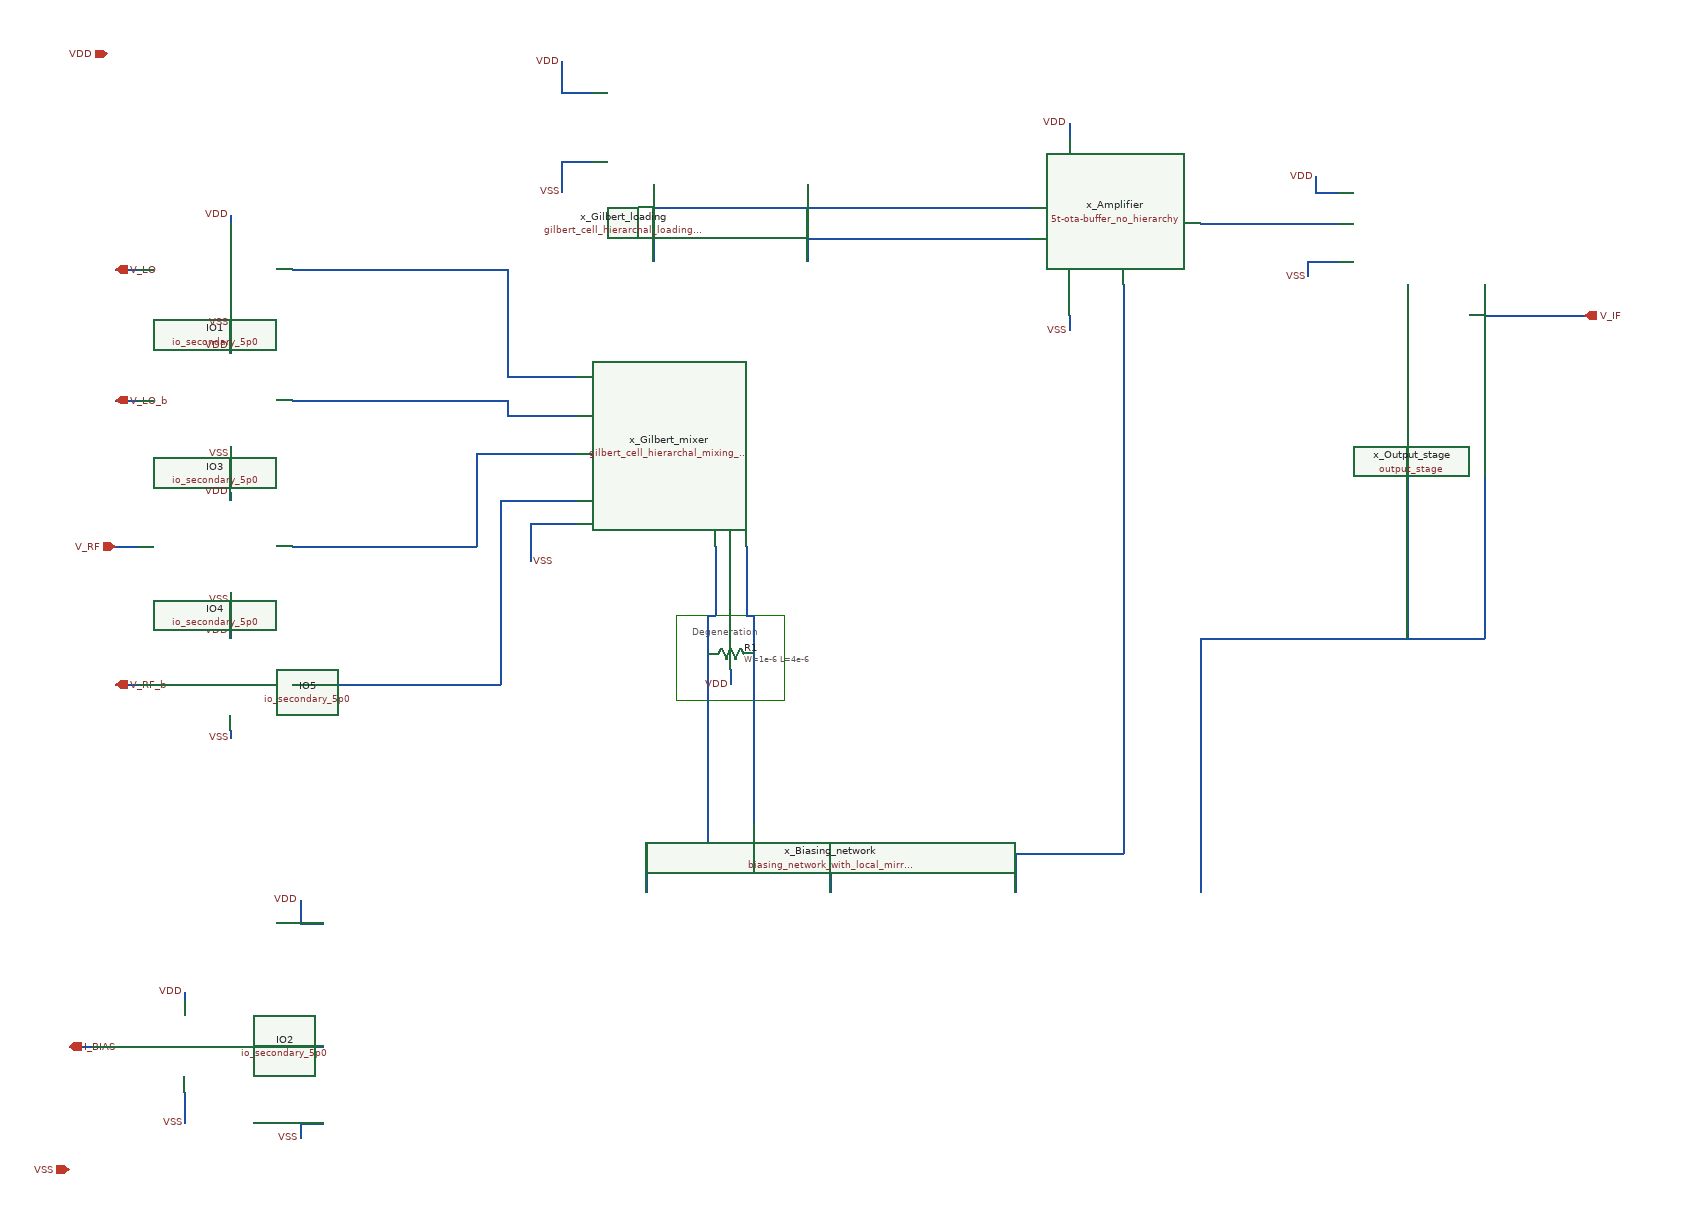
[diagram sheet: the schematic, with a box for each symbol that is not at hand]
v {xschem version=3.4.5 file_version=1.2
}
G {}
K {}
V {}
S {}
E {}
P 4 5 1340 -1230 1480 -1230 1480 -1120 1340 -1120 1340 -1230 {}
T {Degeneration} 1360 -1220 0 0 0.3 0.3 {}
N 1150 -1350 1150 -1300 {
lab=VSS}
N 1390 -1320 1390 -1280 {
lab=#net1}
N 1390 -1280 1390 -1260 {
lab=#net1}
N 1430 -1320 1430 -1260 {
lab=#net2}
N 1310 -1790 1310 -1690 {
lab=#net3}
N 1510 -1790 1510 -1690 {
lab=#net4}
N 1120 -1490 1210 -1490 {
lab=#net5}
N 1120 -1540 1210 -1540 {
lab=#net6}
N 1120 -1440 1210 -1440 {
lab=#net7}
N 1120 -1380 1210 -1380 {
lab=#net8}
N 1150 -1350 1210 -1350 {
lab=VSS}
N 1390 -1260 1390 -1230 {
lab=#net1}
N 1430 -1260 1430 -1230 {
lab=#net2}
N 1410 -1160 1410 -1140 {
lab=VDD}
N 1380 -1180 1380 -1120 {
lab=#net1}
N 1440 -1180 1440 -1130 {
lab=#net2}
N 1380 -1230 1380 -1180 {
lab=#net1}
N 1380 -1230 1390 -1230 {
lab=#net1}
N 1440 -1230 1440 -1180 {
lab=#net2}
N 1430 -1230 1440 -1230 {
lab=#net2}
N 1440 -1130 1440 -1120 {
lab=#net2}
N 1300 -930 1300 -870 {
lab=#net1}
N 1300 -930 1380 -930 {
lab=#net1}
N 1540 -930 1540 -870 {
lab=#net2}
N 1440 -930 1540 -930 {
lab=#net2}
N 1780 -920 1780 -870 {
lab=#net9}
N 1780 -920 1810 -920 {
lab=#net9}
N 850 -830 880 -830 {
lab=VDD}
N 850 -860 850 -830 {
lab=VDD}
N 850 -570 880 -570 {
lab=VSS}
N 1380 -1120 1380 -1020 {
lab=#net1}
N 1440 -1120 1440 -1020 {
lab=#net2}
N 780 -670 880 -670 {
lab=#net10}
N 1380 -960 1380 -930 {
lab=#net1}
N 1440 -960 1440 -930 {
lab=#net2}
N 700 -600 700 -570 {
lab=VSS}
N 700 -610 700 -600 {
lab=VSS}
N 610 -1680 640 -1680 {
lab=V_LO}
N 610 -1510 640 -1510 {
lab=V_LO_b}
N 610 -1320 640 -1320 {
lab=V_RF}
N 610 -1140 640 -1140 {
lab=V_RF_b}
N 1120 -1680 1120 -1540 {
lab=#net6}
N 840 -1680 1120 -1680 {
lab=#net6}
N 840 -1510 1120 -1510 {
lab=#net5}
N 1120 -1510 1120 -1490 {
lab=#net5}
N 840 -1320 1080 -1320 {
lab=#net7}
N 1080 -1440 1080 -1320 {
lab=#net7}
N 1080 -1440 1120 -1440 {
lab=#net7}
N 840 -1140 1110 -1140 {
lab=#net8}
N 1110 -1380 1110 -1140 {
lab=#net8}
N 1110 -1380 1120 -1380 {
lab=#net8}
N 700 -740 700 -730 {
lab=VDD}
N 760 -1210 760 -1200 {
lab=VDD}
N 760 -1390 760 -1380 {
lab=VDD}
N 760 -1580 760 -1570 {
lab=VDD}
N 760 -1750 760 -1740 {
lab=VDD}
N 760 -1080 760 -1070 {
lab=VSS}
N 760 -1260 760 -1250 {
lab=VSS}
N 760 -1450 760 -1440 {
lab=VSS}
N 760 -1620 760 -1610 {
lab=VSS}
N 2480 -1620 2520 -1620 {
lab=V_out}
N 1920 -1660 1920 -1580 {
lab=#net9}
N 1520 -1720 1640 -1720 {
lab=#net4}
N 1520 -1760 1640 -1760 {
lab=#net3}
N 1850 -1870 1850 -1850 {
lab=VDD}
N 1850 -1620 1850 -1600 {
lab=VSS}
N 1640 -1720 1800 -1720 {
lab=#net4}
N 1640 -1760 1780 -1760 {
lab=#net3}
N 1920 -1580 1920 -1360 {
lab=#net9}
N 1920 -1300 1920 -920 {
lab=#net9}
N 1510 -1720 1520 -1720 {
lab=#net4}
N 1310 -1760 1520 -1760 {
lab=#net3}
N 1780 -1760 1800 -1760 {
lab=#net3}
N 1810 -920 1920 -920 {
lab=#net9}
N 2160 -1740 2200 -1740 {
lab=#net11}
N 2020 -1740 2160 -1740 {
lab=#net11}
N 2170 -1800 2170 -1780 {
lab=VDD}
N 2170 -1780 2200 -1780 {
lab=VDD}
N 2390 -1660 2390 -1250 {
lab=V_out}
N 2290 -1660 2290 -1250 {
lab=V_out}
N 2390 -1620 2480 -1620 {
lab=V_out}
N 2020 -1200 2020 -870 {
lab=V_out}
N 2390 -1250 2390 -1200 {
lab=V_out}
N 2020 -1200 2390 -1200 {
lab=V_out}
N 2290 -1250 2290 -1200 {
lab=V_out}
N 2160 -1690 2200 -1690 {
lab=VSS}
N 2160 -1690 2160 -1670 {
lab=VSS}
N 550 -670 580 -670 {
lab=I_BIAS}
N 1380 -1020 1380 -960 {
lab=#net1}
N 1440 -1020 1440 -930 {
lab=#net2}
N 1920 -1360 1920 -1300 {
lab=#net9}
N 850 -570 850 -550 {
lab=VSS}
N 1190 -1910 1230 -1910 {
lab=VDD}
N 1190 -1950 1190 -1910 {
lab=VDD}
N 1190 -1820 1230 -1820 {
lab=VSS}
N 1190 -1820 1190 -1790 {
lab=VSS}
N 1190 -1790 1190 -1780 {
lab=VSS}
C {title-2.sym} 0 0 0 0 {name=l9 author="Time Transcenders" lock=true rev=1.0 page=1}
C {ipin.sym} 610 -1680 2 1 {name=p1 lab=V_LO}
C {ipin.sym} 610 -1510 2 1 {name=p2 lab=V_LO_b
}
C {ipin.sym} 610 -1320 0 0 {name=p3 lab=V_RF}
C {ipin.sym} 610 -1140 2 1 {name=p4 lab=V_RF_b
}
C {libs/A5_core/gilbert_cell_hierarchal_mixing_stage/gilbert_cell_hierarchal_mixing_stage.sym} 1410 -1490 0 0 {name=x_Gilbert_mixer}
C {libs/A5_core/gilbert_cell_hierarchal_loading_stage/gilbert_cell_hierarchal_loading_stage.sym} 1410 -1840 0 0 {name=x_Gilbert_loading}
C {lab_pin.sym} 1410 -1140 3 0 {name=p15 sig_type=std_logic lab=VDD}
C {libs/A5_core/biasing_network_with_local_mirros/biasing_network_with_local_mirros.sym} 1140 -660 0 0 {name=x_Biasing_network}
C {libs/A5_core/io_secondary_5p0/io_secondary_5p0.sym} 840 -1600 0 1 {name=IO1
spiceprefix=X
}
C {libs/A5_core/io_secondary_5p0/io_secondary_5p0.sym} 840 -1430 0 1 {name=IO3
spiceprefix=X
}
C {lab_pin.sym} 700 -740 0 0 {name=p6 sig_type=std_logic lab=VDD}
C {lab_pin.sym} 760 -1210 0 0 {name=p12 sig_type=std_logic lab=VDD}
C {lab_pin.sym} 760 -1390 0 0 {name=p13 sig_type=std_logic lab=VDD}
C {lab_pin.sym} 760 -1580 0 0 {name=p14 sig_type=std_logic lab=VDD}
C {lab_pin.sym} 760 -1750 0 0 {name=p16 sig_type=std_logic lab=VDD}
C {opin.sym} 2520 -1620 0 0 {name=p5 lab=V_IF}
C {libs/A5_core/5t-ota-buffer_no_hierarchy/5t-ota-buffer_no_hierarchy.sym} 1920 -1740 0 0 {name=x_Amplifier}
C {libs/A5_core/output_stage/output_stage.sym} 2330 -1720 0 0 {name=x_Output_stage}
C {symbols/ppolyf_u.sym} 1410 -1180 3 0 {name=R1
W=1e-6
L=4e-6
model=ppolyf_u
spiceprefix=X
m=1
hide_texts=True}
C {ipin.sym} 550 -670 2 1 {name=p8 lab=I_BIAS
}
C {ipin.sym} 600 -1960 0 0 {name=p7 lab=VDD}
C {ipin.sym} 550 -510 0 0 {name=p9 lab=VSS}
C {lab_pin.sym} 850 -550 0 0 {name=p10 sig_type=std_logic lab=VSS}
C {lab_pin.sym} 700 -570 0 0 {name=p11 sig_type=std_logic lab=VSS}
C {lab_pin.sym} 760 -1070 0 0 {name=p17 sig_type=std_logic lab=VSS}
C {lab_pin.sym} 760 -1250 0 0 {name=p18 sig_type=std_logic lab=VSS}
C {lab_pin.sym} 760 -1440 0 0 {name=p19 sig_type=std_logic lab=VSS}
C {lab_pin.sym} 760 -1610 0 0 {name=p20 sig_type=std_logic lab=VSS}
C {lab_pin.sym} 1190 -1780 0 0 {name=p21 sig_type=std_logic lab=VSS}
C {lab_pin.sym} 1850 -1600 0 0 {name=p22 sig_type=std_logic lab=VSS}
C {lab_pin.sym} 2160 -1670 0 0 {name=p23 sig_type=std_logic lab=VSS}
C {lab_pin.sym} 1150 -1300 0 1 {name=p24 sig_type=std_logic lab=VSS}
C {lab_pin.sym} 1190 -1950 0 0 {name=p25 sig_type=std_logic lab=VDD}
C {lab_pin.sym} 1850 -1870 0 0 {name=p26 sig_type=std_logic lab=VDD}
C {lab_pin.sym} 2170 -1800 0 0 {name=p27 sig_type=std_logic lab=VDD}
C {lab_pin.sym} 850 -860 0 0 {name=p28 sig_type=std_logic lab=VDD}
C {libs/A5_core/io_secondary_5p0/io_secondary_5p0.sym} 840 -1240 0 1 {name=IO4
spiceprefix=X
}
C {libs/A5_core/io_secondary_5p0/io_secondary_5p0.sym} 840 -1060 0 1 {name=IO5
spiceprefix=X
}
C {libs/A5_core/io_secondary_5p0/io_secondary_5p0.sym} 780 -590 0 1 {name=IO2
spiceprefix=X
}
